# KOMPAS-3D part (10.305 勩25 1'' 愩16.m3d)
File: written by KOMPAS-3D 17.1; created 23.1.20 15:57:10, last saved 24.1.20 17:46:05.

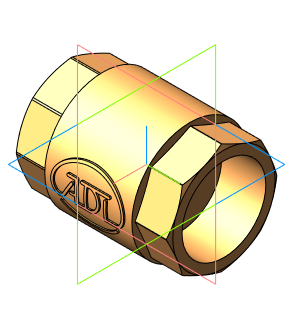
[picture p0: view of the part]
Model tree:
1. Операция без истории:2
